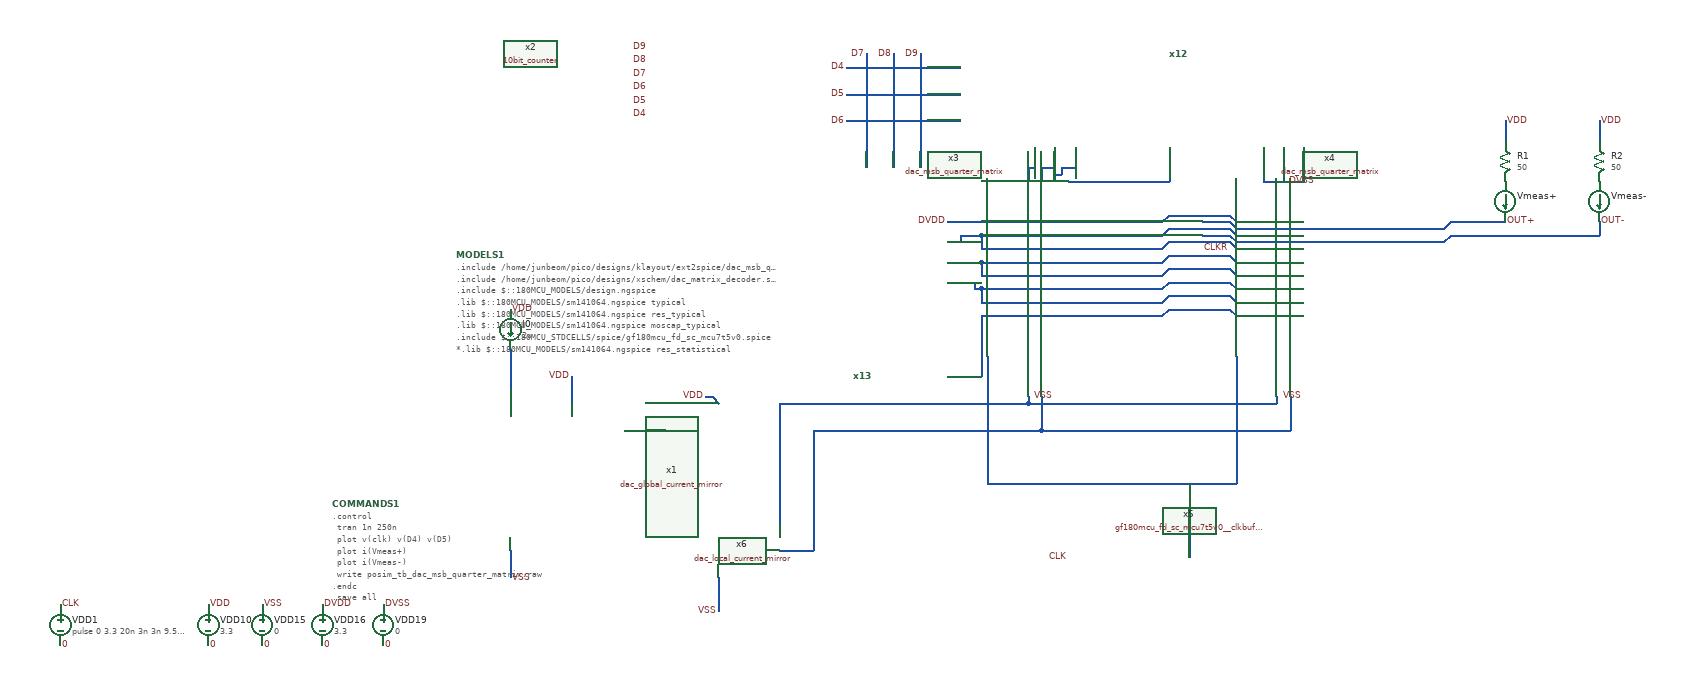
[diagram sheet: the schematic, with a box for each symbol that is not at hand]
v {xschem version=3.4.5 file_version=1.2
}
G {}
K {}
V {}
S {}
E {}
N 1590 -800 1590 -770 {
lab=VDD}
N 1730 -800 1730 -770 {
lab=VDD}
N 1560 -650 1590 -650 {
lab=OUT+}
N 1560 -630 1730 -630 {
lab=OUT-}
N 1730 -650 1730 -630 {
lab=OUT-}
N 110 -160 110 -120 {
lab=VSS}
N 420 -120 420 -70 {
lab=VSS}
N 410 -390 420 -380 {
lab=VDD}
N 310 -340 340 -340 {
lab=#net1}
N 400 -390 410 -390 {
lab=VDD}
N 510 -380 770 -380 {
lab=#net2}
N 510 -380 510 -200 {
lab=#net2}
N 560 -340 770 -340 {
lab=#net3}
N 560 -340 560 -160 {
lab=#net3}
N 510 -160 560 -160 {
lab=#net3}
N 890 -760 890 -730 {
lab=#net4}
N 920 -760 920 -730 {
lab=#net5}
N 950 -760 950 -730 {
lab=#net6}
N 1090 -760 1090 -730 {
lab=#net7}
N 1230 -760 1230 -730 {
lab=#net8}
N 1290 -760 1290 -730 {
lab=#net9}
N 760 -650 780 -650 {
lab=DVDD}
N 760 -420 780 -420 {
lab=#net10}
N 770 -380 780 -380 {
lab=#net2}
N 770 -340 780 -340 {
lab=#net3}
N 610 -880 780 -880 {
lab=D4}
N 610 -840 780 -840 {
lab=D5}
N 610 -800 780 -800 {
lab=D6}
N 640 -900 640 -730 {
lab=D7}
N 680 -900 680 -730 {
lab=D8}
N 720 -900 720 -730 {
lab=D9}
N 110 -460 110 -400 {
lab=#net11}
N 200 -410 200 -380 {
lab=VDD}
N 200 -420 200 -410 {
lab=VDD}
N 280 -340 310 -340 {
lab=#net1}
N 780 -650 820 -650 {
lab=DVDD}
N 810 -610 820 -610 {
lab=#net12}
N 810 -570 820 -570 {
lab=#net13}
N 810 -550 820 -550 {
lab=#net14}
N 810 -530 820 -530 {
lab=#net14}
N 780 -420 810 -420 {
lab=#net10}
N 810 -510 810 -420 {
lab=#net10}
N 810 -510 820 -510 {
lab=#net10}
N 780 -380 880 -380 {
lab=#net2}
N 880 -390 880 -380 {
lab=#net2}
N 780 -340 900 -340 {
lab=#net3}
N 900 -390 900 -340 {
lab=#net3}
N 880 -730 890 -730 {
lab=#net4}
N 880 -730 880 -710 {
lab=#net4}
N 900 -730 920 -730 {
lab=#net5}
N 900 -730 900 -710 {
lab=#net5}
N 930 -730 950 -730 {
lab=#net6}
N 930 -730 930 -720 {
lab=#net6}
N 920 -720 930 -720 {
lab=#net6}
N 920 -720 920 -710 {
lab=#net6}
N 940 -710 1090 -710 {
lab=#net7}
N 1090 -730 1090 -710 {
lab=#net7}
N 810 -630 820 -630 {
lab=#net12}
N 810 -590 820 -590 {
lab=#net13}
N 760 -620 780 -620 {
lab=#net12}
N 760 -590 770 -590 {
lab=#net13}
N 820 -650 1080 -650 {
lab=DVDD}
N 1080 -650 1090 -660 {
lab=DVDD}
N 1090 -660 1180 -660 {
lab=DVDD}
N 1180 -660 1190 -650 {
lab=DVDD}
N 820 -630 1080 -630 {
lab=#net12}
N 780 -630 780 -620 {
lab=#net12}
N 780 -630 810 -630 {
lab=#net12}
N 810 -630 810 -610 {
lab=#net12}
N 770 -590 810 -590 {
lab=#net13}
N 810 -590 810 -570 {
lab=#net13}
N 760 -560 800 -560 {
lab=#net14}
N 800 -560 800 -550 {
lab=#net14}
N 800 -550 810 -550 {
lab=#net14}
N 810 -550 810 -530 {
lab=#net14}
N 1230 -730 1230 -710 {
lab=#net8}
N 1230 -710 1250 -710 {
lab=#net8}
N 1260 -760 1260 -710 {
lab=#net15}
N 1260 -710 1270 -710 {
lab=#net15}
N 1290 -730 1290 -710 {
lab=#net9}
N 1080 -630 1090 -640 {
lab=#net12}
N 1090 -640 1180 -640 {
lab=#net12}
N 1180 -640 1190 -630 {
lab=#net12}
N 820 -610 1080 -610 {
lab=#net12}
N 1080 -610 1090 -620 {
lab=#net12}
N 1090 -620 1180 -620 {
lab=#net12}
N 1180 -620 1190 -610 {
lab=#net12}
N 820 -590 1080 -590 {
lab=#net13}
N 1080 -590 1090 -600 {
lab=#net13}
N 1090 -600 1180 -600 {
lab=#net13}
N 1180 -600 1190 -590 {
lab=#net13}
N 1080 -570 1090 -580 {
lab=#net13}
N 1090 -580 1180 -580 {
lab=#net13}
N 1180 -580 1190 -570 {
lab=#net13}
N 1080 -550 1090 -560 {
lab=#net14}
N 1090 -560 1180 -560 {
lab=#net14}
N 1180 -560 1190 -550 {
lab=#net14}
N 1080 -530 1090 -540 {
lab=#net14}
N 1090 -540 1180 -540 {
lab=#net14}
N 1180 -540 1190 -530 {
lab=#net14}
N 1080 -510 1090 -520 {
lab=#net10}
N 1090 -520 1180 -520 {
lab=#net10}
N 1180 -520 1190 -510 {
lab=#net10}
N 820 -570 1080 -570 {
lab=#net13}
N 820 -550 1080 -550 {
lab=#net14}
N 820 -530 1080 -530 {
lab=#net14}
N 820 -510 1080 -510 {
lab=#net10}
N 880 -380 1250 -380 {
lab=#net2}
N 1250 -390 1250 -380 {
lab=#net2}
N 900 -340 1270 -340 {
lab=#net3}
N 1270 -390 1270 -340 {
lab=#net3}
N 1140 -650 1180 -650 {
lab=OUT+}
N 1180 -650 1190 -640 {
lab=OUT+}
N 1190 -640 1500 -640 {
lab=OUT+}
N 1500 -640 1510 -650 {
lab=OUT+}
N 1510 -650 1560 -650 {
lab=OUT+}
N 1140 -630 1180 -630 {
lab=OUT-}
N 1180 -630 1190 -620 {
lab=OUT-}
N 1190 -620 1500 -620 {
lab=OUT-}
N 1500 -620 1510 -630 {
lab=OUT-}
N 1510 -630 1560 -630 {
lab=OUT-}
N 820 -450 820 -260 {
lab=#net16}
N 820 -260 1190 -260 {
lab=#net16}
N 1190 -450 1190 -260 {
lab=#net16}
N 1120 -260 1120 -150 {
lab=#net16}
C {devices/lab_pin.sym} -560 -80 0 1 {name=p607 sig_type=std_logic lab=CLK}
C {devices/lab_pin.sym} -560 -20 0 1 {name=p608 sig_type=std_logic lab=0}
C {devices/vsource.sym} -340 -50 0 0 {name=VDD10 value=3.3}
C {devices/lab_pin.sym} -340 -20 0 1 {name=p621 sig_type=std_logic lab=0}
C {devices/lab_pin.sym} -340 -80 0 1 {name=p622 sig_type=std_logic lab=VDD}
C {devices/vsource.sym} -260 -50 0 0 {name=VDD15 value=0}
C {devices/lab_pin.sym} -260 -20 0 1 {name=p8 sig_type=std_logic lab=0}
C {devices/lab_pin.sym} -260 -80 0 1 {name=p9 sig_type=std_logic lab=VSS}
C {devices/vsource.sym} -170 -50 0 0 {name=VDD16 value=3.3}
C {devices/lab_pin.sym} -170 -20 0 1 {name=p10 sig_type=std_logic lab=0}
C {devices/lab_pin.sym} -170 -80 0 1 {name=p11 sig_type=std_logic lab=DVDD}
C {devices/vsource.sym} -80 -50 0 0 {name=VDD19 value=0}
C {devices/lab_pin.sym} -80 -20 0 1 {name=p16 sig_type=std_logic lab=0}
C {devices/lab_pin.sym} -80 -80 0 1 {name=p17 sig_type=std_logic lab=DVSS}
C {devices/isource.sym} 110 -490 0 0 {name=I0 value=2u}
C {devices/lab_pin.sym} 110 -520 0 1 {name=p19 sig_type=std_logic lab=VDD}
C {devices/lab_pin.sym} 1590 -650 0 1 {name=p20 sig_type=std_logic lab=OUT+}
C {devices/lab_pin.sym} 1730 -650 0 1 {name=p21 sig_type=std_logic lab=OUT-}
C {devices/lab_pin.sym} 1590 -800 0 1 {name=p22 sig_type=std_logic lab=VDD}
C {devices/lab_pin.sym} 1730 -800 0 1 {name=p23 sig_type=std_logic lab=VDD}
C {devices/res.sym} 1590 -740 0 0 {name=R1
value=50
footprint=1206
device=resistor
m=1}
C {devices/res.sym} 1730 -740 0 0 {name=R2
value=50
footprint=1206
device=resistor
m=1}
C {devices/ammeter.sym} 1590 -680 0 0 {name=Vmeas+}
C {devices/ammeter.sym} 1730 -680 0 0 {name=Vmeas-}
C {devices/simulator_commands.sym} -155 -230 0 0 {name=COMMANDS1
only_toplevel=false
value="

.control
	tran 1n 250n
	plot v(clk) v(D4) v(D5)
	plot i(Vmeas+) 
	plot i(Vmeas-)
	write posim_tb_dac_msb_quarter_matrix.raw
.endc
.save all

"}
C {devices/vsource.sym} -560 -50 0 0 {name=VDD1 value="pulse 0 3.3 20n 3n 3n 9.5n 25n"}
C {dac_global_current_mirror.sym} 230 -140 0 0 {name=x1}
C {dac_local_current_mirror.sym} 320 -70 0 0 {name=x6}
C {devices/lab_pin.sym} 420 -70 3 0 {name=p25 sig_type=std_logic lab=VSS}
C {devices/lab_pin.sym} 400 -390 0 0 {name=p42 sig_type=std_logic lab=VDD}
C {dac_matrix_decoder.sym} 1090 -900 3 1 {name=x12 DVDD=DVDD DVSS=DVSS}
C {dac_matrix_decoder.sym} 620 -420 0 0 {name=x13 DVDD=DVDD DVSS=DVSS}
C {devices/lab_pin.sym} 760 -650 0 0 {name=p55 sig_type=std_logic lab=DVDD}
C {10bit_counter.sym} 140 -900 0 0 {name=x2}
C {devices/lab_pin.sym} 290 -810 0 1 {name=p3 sig_type=std_logic lab=D4}
C {devices/lab_pin.sym} 290 -830 0 1 {name=p12 sig_type=std_logic lab=D5}
C {devices/lab_pin.sym} 290 -850 0 1 {name=p13 sig_type=std_logic lab=D6}
C {devices/lab_pin.sym} 290 -870 2 0 {name=p14 sig_type=std_logic lab=D7}
C {devices/lab_pin.sym} 290 -890 2 0 {name=p15 sig_type=std_logic lab=D8}
C {devices/lab_pin.sym} 290 -910 2 0 {name=p28 sig_type=std_logic lab=D9}
C {devices/lab_pin.sym} 200 -420 1 0 {name=p2 sig_type=std_logic lab=VDD}
C {devices/lab_pin.sym} 110 -120 0 1 {name=p18 sig_type=std_logic lab=VSS}
C {devices/code_shown.sym} 30 -600 2 0 {name=MODELS1
only_toplevel=true
format="tcleval( @value )"
value="
.include /home/junbeom/pico/designs/klayout/ext2spice/dac_msb_quarter_matrix/dac_msb_quarter_matrix_pex_extracted.spice
.include /home/junbeom/pico/designs/xschem/dac_matrix_decoder.spice
.include $::180MCU_MODELS/design.ngspice
.lib $::180MCU_MODELS/sm141064.ngspice typical
.lib $::180MCU_MODELS/sm141064.ngspice res_typical
.lib $::180MCU_MODELS/sm141064.ngspice moscap_typical
.include $::180MCU_STDCELLS/spice/gf180mcu_fd_sc_mcu7t5v0.spice
*.lib $::180MCU_MODELS/sm141064.ngspice res_statistical
"}
C {devices/lab_pin.sym} 610 -800 0 0 {name=p4 sig_type=std_logic lab=D6}
C {devices/lab_pin.sym} 610 -840 0 0 {name=p5 sig_type=std_logic lab=D5}
C {devices/lab_pin.sym} 610 -880 0 0 {name=p6 sig_type=std_logic lab=D4}
C {devices/lab_pin.sym} 640 -900 1 0 {name=p7 sig_type=std_logic lab=D7}
C {devices/lab_pin.sym} 680 -900 1 0 {name=p26 sig_type=std_logic lab=D8}
C {devices/lab_pin.sym} 720 -900 1 0 {name=p27 sig_type=std_logic lab=D9}
C {posim/dac_msb_quarter_matrix.sym} 980 -550 0 0 {name=x3 DVDD=DVDD DVSS=DVSS}
C {devices/lab_pin.sym} 920 -390 3 0 {name=p1 sig_type=std_logic lab=VSS}
C {posim/dac_msb_quarter_matrix.sym} 1350 -550 0 0 {name=x4 DVDD=DVDD DVSS=DVSS}
C {devices/lab_pin.sym} 1310 -710 1 0 {name=p29 sig_type=std_logic lab=DVSS}
C {devices/lab_pin.sym} 1290 -390 3 0 {name=p31 sig_type=std_logic lab=VSS}
C {std_cell/gf180mcu_fd_sc_mcu7t5v0__clkbuf_16.sym} 1030 -150 0 0 {name=x5 VDD=DVDD VNW=DVDD VPW=DVSS VSS=DVSS}
C {devices/lab_pin.sym} 940 -150 0 0 {name=p24 sig_type=std_logic lab=CLK}
C {devices/lab_pin.sym} 1140 -610 2 0 {name=p30 sig_type=std_logic lab=CLKR}
